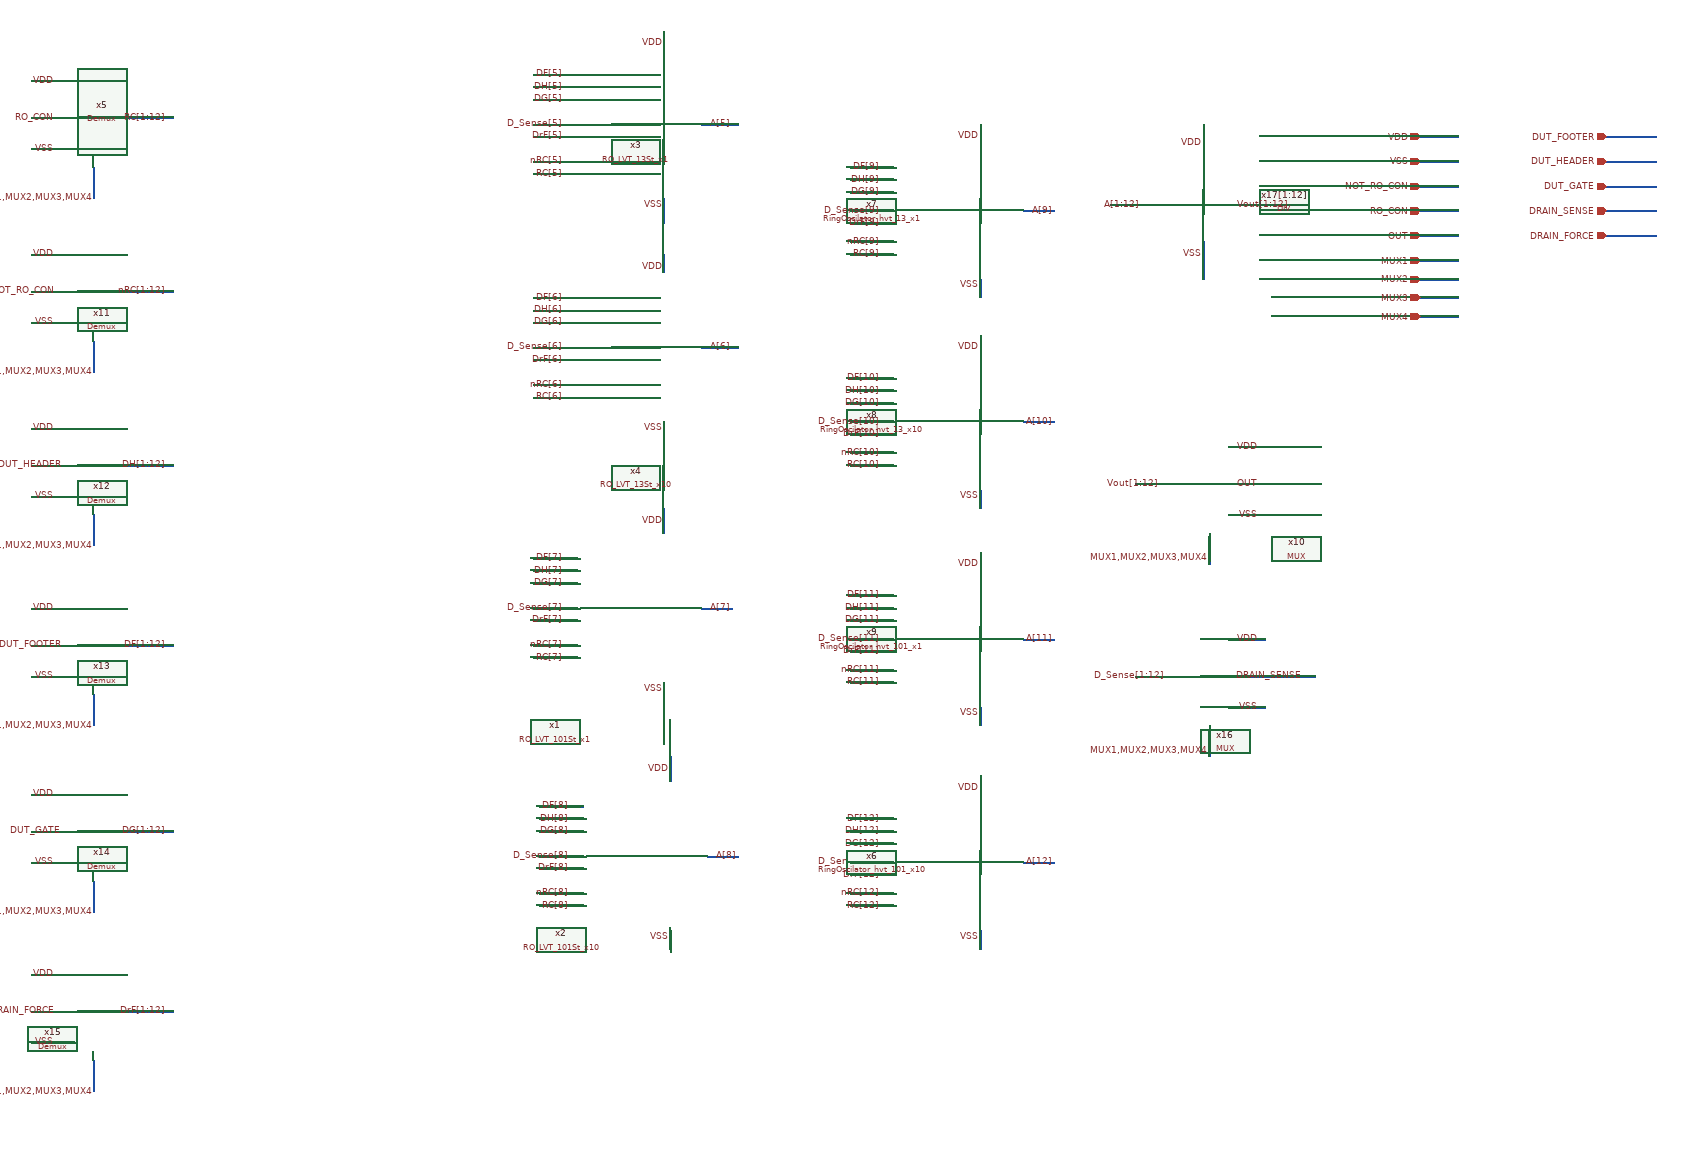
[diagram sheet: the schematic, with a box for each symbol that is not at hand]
v {xschem version=3.4.6RC file_version=1.2
}
G {}
K {}
V {}
S {}
E {}
N -850 650 -850 690 {
lab=VDD}
N -1060 730 -990 730 {
lab=DF[8]}
N -1060 750 -990 750 {
lab=DH[8]}
N -1060 770 -990 770 {
lab=DG[8]}
N -1060 810 -990 810 {
lab=D_Sense[8]}
N -1060 830 -990 830 {
lab=DrF[8]}
N -1060 870 -990 870 {
lab=nRC[8]}
N -1060 890 -990 890 {
lab=RC[8]}
N -790 810 -740 810 {
lab=A[8]}
N -850 930 -850 960 {
lab=VSS}
N -860 -520 -860 -490 {
lab=VDD}
N -860 -250 -860 -210 {
lab=VSS}
N -800 -370 -740 -370 {
lab=A[5]}
N 360 -350 420 -350 {
lab=VDD}
N 360 -310 420 -310 {
lab=VSS}
N 360 -270 420 -270 {
lab=NOT_RO_CON}
N 360 -230 420 -230 {
lab=RO_CON}
N 660 -350 740 -350 {
lab=DUT_FOOTER}
N 660 -310 740 -310 {
lab=DUT_HEADER}
N 660 -270 740 -270 {
lab=DUT_GATE}
N 660 -230 740 -230 {
lab=DRAIN_SENSE}
N 660 -190 740 -190 {
lab=DRAIN_FORCE}
N 360 -190 420 -190 {
lab=OUT}
N 360 -150 420 -150 {
lab=MUX1}
N -860 -160 -860 -130 {
lab=VDD}
N -860 110 -860 150 {
lab=VSS}
N -800 -10 -740 -10 {
lab=A[6]}
N -860 250 -860 290 {
lab=VDD}
N -800 410 -750 410 {
lab=A[7]}
N -860 530 -860 560 {
lab=VSS}
N -350 320 -350 360 {
lab=VDD}
N -280 460 -230 460 {
lab=A[11]}
N -350 570 -350 600 {
lab=VSS}
N -350 680 -350 720 {
lab=VDD}
N -560 750 -490 750 {
lab=DF[12]}
N -560 770 -490 770 {
lab=DH[12]}
N -560 790 -490 790 {
lab=DG[12]}
N -560 820 -490 820 {
lab=D_Sense[12]}
N -560 840 -490 840 {
lab=DrF[12]}
N -560 870 -490 870 {
lab=nRC[12]}
N -560 890 -490 890 {
lab=RC[12]}
N -280 820 -230 820 {
lab=A[12]}
N -350 930 -350 960 {
lab=VSS}
N -350 -370 -350 -330 {
lab=VDD}
N -280 -230 -230 -230 {
lab=A[9]}
N -350 -120 -350 -90 {
lab=VSS}
N -350 -30 -350 10 {
lab=VDD}
N -280 110 -230 110 {
lab=A[10]}
N -350 220 -350 250 {
lab=VSS}
N 50 150 110 150 {
lab=VDD}
N 50 210 110 210 {
lab=OUT}
N 50 260 110 260 {
lab=VSS}
N 20 290 20 340 {
lab=MUX1,MUX2,MUX3,MUX4}
N -100 210 -20 210 {
lab=Vout[1:12]}
N -1880 -380 -1810 -380 {
lab=RO_CON}
N -1880 -330 -1810 -330 {
lab=VSS}
N -1880 -440 -1810 -440 {
lab=VDD}
N -1780 -300 -1780 -250 {
lab=MUX1,MUX2,MUX3,MUX4}
N -1740 -380 -1650 -380 {
lab=RC[1:12]}
N -1880 -100 -1810 -100 {
lab=NOT_RO_CON}
N -1880 -50 -1810 -50 {
lab=VSS}
N -1880 -160 -1810 -160 {
lab=VDD}
N -1780 -20 -1780 30 {
lab=MUX1,MUX2,MUX3,MUX4}
N -1740 -100 -1650 -100 {
lab=nRC[1:12]}
N -1880 180 -1810 180 {
lab=DUT_HEADER}
N -1880 230 -1810 230 {
lab=VSS}
N -1880 120 -1810 120 {
lab=VDD}
N -1780 260 -1780 310 {
lab=MUX1,MUX2,MUX3,MUX4}
N -1740 180 -1650 180 {
lab=DH[1:12]}
N -1880 470 -1810 470 {
lab=DUT_FOOTER}
N -1880 520 -1810 520 {
lab=VSS}
N -1880 410 -1810 410 {
lab=VDD}
N -1780 550 -1780 600 {
lab=MUX1,MUX2,MUX3,MUX4}
N -1740 470 -1650 470 {
lab=DF[1:12]}
N -1880 770 -1810 770 {
lab=DUT_GATE}
N -1880 820 -1810 820 {
lab=VSS}
N -1880 710 -1810 710 {
lab=VDD}
N -1780 850 -1780 900 {
lab=MUX1,MUX2,MUX3,MUX4}
N -1740 770 -1650 770 {
lab=DG[1:12]}
N -1880 1060 -1810 1060 {
lab=DRAIN_FORCE}
N -1880 1110 -1810 1110 {
lab=VSS}
N -1880 1000 -1810 1000 {
lab=VDD}
N -1780 1140 -1780 1190 {
lab=MUX1,MUX2,MUX3,MUX4}
N -1740 1060 -1650 1060 {
lab=DrF[1:12]}
N 360 -120 420 -120 {
lab=MUX2}
N 360 -90 420 -90 {
lab=MUX3}
N 360 -60 420 -60 {
lab=MUX4}
N 50 460 110 460 {
lab=VDD}
N 50 520 110 520 {
lab=DRAIN_SENSE}
N 50 570 110 570 {
lab=VSS}
N 20 600 20 650 {
lab=MUX1,MUX2,MUX3,MUX4}
N -100 520 -20 520 {
lab=D_Sense[1:12]}
N 110 520 190 520 {
lab=DRAIN_SENSE}
N -560 390 -490 390 {
lab=DF[11]}
N -560 410 -490 410 {
lab=DH[11]}
N -560 430 -490 430 {
lab=DG[11]}
N -560 460 -490 460 {
lab=D_Sense[11]}
N -560 480 -490 480 {
lab=DrF[11]}
N -560 510 -490 510 {
lab=nRC[11]}
N -560 530 -490 530 {
lab=RC[11]}
N -560 40 -490 40 {
lab=DF[10]}
N -560 60 -490 60 {
lab=DH[10]}
N -560 80 -490 80 {
lab=DG[10]}
N -560 110 -490 110 {
lab=D_Sense[10]}
N -560 130 -490 130 {
lab=DrF[10]}
N -560 160 -490 160 {
lab=nRC[10]}
N -560 180 -490 180 {
lab=RC[10]}
N -560 -300 -490 -300 {
lab=DF[9]}
N -560 -280 -490 -280 {
lab=DH[9]}
N -560 -260 -490 -260 {
lab=DG[9]}
N -560 -230 -490 -230 {
lab=D_Sense[9]}
N -560 -210 -490 -210 {
lab=DrF[9]}
N -560 -180 -490 -180 {
lab=nRC[9]}
N -560 -160 -490 -160 {
lab=RC[9]}
N -1070 330 -1000 330 {
lab=DF[7]}
N -1070 350 -1000 350 {
lab=DH[7]}
N -1070 370 -1000 370 {
lab=DG[7]}
N -1070 410 -1000 410 {
lab=D_Sense[7]}
N -1070 430 -1000 430 {
lab=DrF[7]}
N -1070 470 -1000 470 {
lab=nRC[7]}
N -1070 490 -1000 490 {
lab=RC[7]}
N -1070 -90 -1000 -90 {
lab=DF[6]}
N -1070 -70 -1000 -70 {
lab=DH[6]}
N -1070 -50 -1000 -50 {
lab=DG[6]}
N -1070 -10 -1000 -10 {
lab=D_Sense[6]}
N -1070 10 -1000 10 {
lab=DrF[6]}
N -1070 50 -1000 50 {
lab=nRC[6]}
N -1070 70 -1000 70 {
lab=RC[6]}
N -1070 -450 -1000 -450 {
lab=DF[5]}
N -1070 -430 -1000 -430 {
lab=DH[5]}
N -1070 -410 -1000 -410 {
lab=DG[5]}
N -1070 -370 -1000 -370 {
lab=D_Sense[5]}
N -1070 -350 -1000 -350 {
lab=DrF[5]}
N -1070 -310 -1000 -310 {
lab=nRC[5]}
N -1070 -290 -1000 -290 {
lab=RC[5]}
N -140 -240 -60 -240 {
lab=#net1}
N 10 -180 10 -120 {
lab=#net2}
N 10 -370 10 -300 {
lab=#net3}
N 60 -240 150 -240 {
lab=#net4}
C {lab_wire.sym} -850 670 0 0 {name=p2 sig_type=std_logic lab=VDD}
C {lab_wire.sym} -860 -500 0 0 {name=p3 sig_type=std_logic lab=VDD}
C {lab_wire.sym} -860 -240 2 1 {name=p4 sig_type=std_logic lab=VSS}
C {lab_wire.sym} -850 940 2 1 {name=p5 sig_type=std_logic lab=VSS}
C {lab_wire.sym} -740 810 0 0 {name=p29 sig_type=std_logic lab=A[8]}
C {lab_wire.sym} -750 -370 0 0 {name=p30 sig_type=std_logic lab=A[5]}
C {iopin.sym} 360 -350 2 0 {name=p81 lab=VDD}
C {iopin.sym} 360 -310 2 0 {name=p82 lab=VSS}
C {iopin.sym} 360 -270 2 0 {name=p83 lab=NOT_RO_CON}
C {iopin.sym} 360 -230 2 0 {name=p84 lab=RO_CON}
C {iopin.sym} 660 -350 2 0 {name=p85 lab=DUT_FOOTER}
C {iopin.sym} 660 -310 2 0 {name=p86 lab=DUT_HEADER}
C {iopin.sym} 660 -270 2 0 {name=p87 lab=DUT_GATE}
C {iopin.sym} 660 -230 2 0 {name=p88 lab=DRAIN_SENSE}
C {iopin.sym} 660 -190 2 0 {name=p89 lab=DRAIN_FORCE}
C {iopin.sym} 360 -190 2 0 {name=p90 lab=OUT}
C {iopin.sym} 360 -150 2 0 {name=p37 lab=MUX1}
C {/foss/designs/RO_Aging_UNICASS/LVT/RO_LVT_101St_x10/RO_LVT_101St_x10.sym} -990 930 0 0 {name=x2}
C {/foss/designs/RO_Aging_UNICASS/LVT/RO_LVT_13St_x1/RO_LVT_13St_x1.sym} -1020 -250 0 0 {name=x3}
C {lab_wire.sym} -860 -140 0 0 {name=p38 sig_type=std_logic lab=VDD}
C {lab_wire.sym} -860 120 2 1 {name=p39 sig_type=std_logic lab=VSS}
C {lab_wire.sym} -750 -10 0 0 {name=p47 sig_type=std_logic lab=A[6]}
C {/foss/designs/RO_Aging_UNICASS/LVT/RO_LVT_13St_x10/RO_LVT_13St_x10.sym} -1020 110 0 0 {name=x4}
C {lab_wire.sym} -860 270 0 0 {name=p1 sig_type=std_logic lab=VDD}
C {lab_wire.sym} -860 540 2 1 {name=p6 sig_type=std_logic lab=VSS}
C {lab_wire.sym} -750 410 0 0 {name=p48 sig_type=std_logic lab=A[7]}
C {/foss/designs/RO_Aging_UNICASS/LVT/RO_LVT_101St_x1/RO_LVT_101St_x1.sym} -1000 530 0 0 {name=x1}
C {lab_wire.sym} -350 340 0 0 {name=p78 sig_type=std_logic lab=VDD}
C {lab_wire.sym} -350 580 2 1 {name=p79 sig_type=std_logic lab=VSS}
C {lab_wire.sym} -230 460 0 0 {name=p97 sig_type=std_logic lab=A[11]}
C {/foss/designs/RO_Aging_UNICASS/HVT/RingOscilator_hvt_101_x1/RingOscilator_hvt_101_x1.sym} -380 460 0 0 {name=x9}
C {lab_wire.sym} -350 700 0 0 {name=p28 sig_type=std_logic lab=VDD}
C {lab_wire.sym} -350 940 2 1 {name=p49 sig_type=std_logic lab=VSS}
C {lab_wire.sym} -510 770 0 0 {name=p50 sig_type=std_logic lab=DH[12]}
C {lab_wire.sym} -510 750 0 0 {name=p51 sig_type=std_logic lab=DF[12]}
C {lab_wire.sym} -510 790 0 0 {name=p52 sig_type=std_logic lab=DG[12]}
C {lab_wire.sym} -510 820 0 0 {name=p53 sig_type=std_logic lab=D_Sense[12]}
C {lab_wire.sym} -510 840 0 0 {name=p54 sig_type=std_logic lab=DrF[12]}
C {lab_wire.sym} -230 820 0 0 {name=p57 sig_type=std_logic lab=A[12]}
C {lab_wire.sym} -350 -350 0 0 {name=p58 sig_type=std_logic lab=VDD}
C {lab_wire.sym} -350 -110 2 1 {name=p59 sig_type=std_logic lab=VSS}
C {lab_wire.sym} -230 -230 0 0 {name=p67 sig_type=std_logic lab=A[9]}
C {lab_wire.sym} -350 -10 0 0 {name=p68 sig_type=std_logic lab=VDD}
C {lab_wire.sym} -350 230 2 1 {name=p69 sig_type=std_logic lab=VSS}
C {lab_wire.sym} -230 110 0 0 {name=p77 sig_type=std_logic lab=A[10]}
C {/foss/designs/RO_Aging_UNICASS/HVT/RingOscilator_hvt_101_x10/RingOscilator_hvt_101_x10.sym} -380 820 0 0 {name=x6}
C {/foss/designs/RO_Aging_UNICASS/HVT/RingOscilator_hvt_13_x1/RingOscilator_hvt_13_x1.sym} -380 -230 0 0 {name=x7}
C {/foss/designs/RO_Aging_UNICASS/HVT/RingOscilator_hvt_13_x10/RingOscilator_hvt_13_x10.sym} -380 110 0 0 {name=x8}
C {/foss/designs/RO_Aging_UNICASS/MUX/MUX.sym} 0 200 0 0 {name=x10}
C {lab_wire.sym} 100 150 0 0 {name=p31 sig_type=std_logic lab=VDD}
C {lab_wire.sym} 100 260 2 1 {name=p32 sig_type=std_logic lab=VSS}
C {lab_wire.sym} 100 210 0 0 {name=p33 sig_type=std_logic lab=OUT}
C {/foss/designs/RO_Aging_UNICASS/MUX/Demux.sym} -1780 -220 0 0 {name=x5}
C {lab_wire.sym} -1840 -440 0 0 {name=p34 sig_type=std_logic lab=VDD}
C {lab_wire.sym} -1840 -330 0 0 {name=p35 sig_type=std_logic lab=VSS}
C {lab_wire.sym} -1840 -380 0 0 {name=p36 sig_type=std_logic lab=RO_CON}
C {lab_wire.sym} -1780 -250 0 0 {name=p98 sig_type=std_logic lab=MUX1,MUX2,MUX3,MUX4}
C {/foss/designs/RO_Aging_UNICASS/MUX/Demux.sym} -1780 60 0 0 {name=x11}
C {lab_wire.sym} -1840 -160 0 0 {name=p99 sig_type=std_logic lab=VDD}
C {lab_wire.sym} -1840 -50 0 0 {name=p100 sig_type=std_logic lab=VSS}
C {lab_wire.sym} -1840 -100 0 0 {name=p101 sig_type=std_logic lab=NOT_RO_CON}
C {lab_wire.sym} -1780 30 0 0 {name=p102 sig_type=std_logic lab=MUX1,MUX2,MUX3,MUX4}
C {/foss/designs/RO_Aging_UNICASS/MUX/Demux.sym} -1780 340 0 0 {name=x12}
C {lab_wire.sym} -1840 120 0 0 {name=p103 sig_type=std_logic lab=VDD}
C {lab_wire.sym} -1840 230 0 0 {name=p104 sig_type=std_logic lab=VSS}
C {lab_wire.sym} -1780 310 0 0 {name=p106 sig_type=std_logic lab=MUX1,MUX2,MUX3,MUX4}
C {/foss/designs/RO_Aging_UNICASS/MUX/Demux.sym} -1780 630 0 0 {name=x13}
C {lab_wire.sym} -1840 410 0 0 {name=p107 sig_type=std_logic lab=VDD}
C {lab_wire.sym} -1840 520 0 0 {name=p108 sig_type=std_logic lab=VSS}
C {lab_wire.sym} -1780 600 0 0 {name=p110 sig_type=std_logic lab=MUX1,MUX2,MUX3,MUX4}
C {/foss/designs/RO_Aging_UNICASS/MUX/Demux.sym} -1780 930 0 0 {name=x14}
C {lab_wire.sym} -1840 710 0 0 {name=p111 sig_type=std_logic lab=VDD}
C {lab_wire.sym} -1840 820 0 0 {name=p112 sig_type=std_logic lab=VSS}
C {lab_wire.sym} -1780 900 0 0 {name=p114 sig_type=std_logic lab=MUX1,MUX2,MUX3,MUX4}
C {/foss/designs/RO_Aging_UNICASS/MUX/Demux.sym} -1780 1220 0 0 {name=x15}
C {lab_wire.sym} -1840 1000 0 0 {name=p115 sig_type=std_logic lab=VDD}
C {lab_wire.sym} -1840 1110 0 0 {name=p116 sig_type=std_logic lab=VSS}
C {lab_wire.sym} -1780 1190 0 0 {name=p118 sig_type=std_logic lab=MUX1,MUX2,MUX3,MUX4}
C {lab_wire.sym} -1830 180 0 0 {name=p105 sig_type=std_logic lab=DUT_HEADER}
C {lab_wire.sym} -1830 470 0 0 {name=p109 sig_type=std_logic lab=DUT_FOOTER}
C {lab_wire.sym} -1830 770 0 0 {name=p113 sig_type=std_logic lab=DUT_GATE}
C {lab_wire.sym} -1840 1060 0 0 {name=p117 sig_type=std_logic lab=DRAIN_FORCE}
C {iopin.sym} 360 -120 2 0 {name=p119 lab=MUX2}
C {iopin.sym} 360 -90 2 0 {name=p120 lab=MUX3}
C {iopin.sym} 360 -60 2 0 {name=p121 lab=MUX4}
C {/foss/designs/RO_Aging_UNICASS/MUX/MUX.sym} 0 510 0 0 {name=x16}
C {lab_wire.sym} 100 460 0 0 {name=p122 sig_type=std_logic lab=VDD}
C {lab_wire.sym} 100 570 2 1 {name=p123 sig_type=std_logic lab=VSS}
C {lab_wire.sym} 170 520 0 0 {name=p124 sig_type=std_logic lab=DRAIN_SENSE}
C {lab_wire.sym} 20 330 0 0 {name=p125 sig_type=std_logic lab=MUX1,MUX2,MUX3,MUX4}
C {lab_wire.sym} 20 640 0 0 {name=p126 sig_type=std_logic lab=MUX1,MUX2,MUX3,MUX4}
C {lab_wire.sym} -1660 -380 0 0 {name=p127 sig_type=std_logic lab=RC[1:12]}
C {lab_wire.sym} -1660 -100 0 0 {name=p128 sig_type=std_logic lab=nRC[1:12]}
C {lab_wire.sym} -1660 180 0 0 {name=p129 sig_type=std_logic lab=DH[1:12]}
C {lab_wire.sym} -1660 470 0 0 {name=p130 sig_type=std_logic lab=DF[1:12]}
C {lab_wire.sym} -1660 770 0 0 {name=p131 sig_type=std_logic lab=DG[1:12]}
C {lab_wire.sym} -1660 1060 0 0 {name=p132 sig_type=std_logic lab=DrF[1:12]}
C {lab_wire.sym} -510 890 0 0 {name=p133 sig_type=std_logic lab=RC[12]}
C {lab_wire.sym} -510 870 0 0 {name=p55 sig_type=std_logic lab=nRC[12]}
C {lab_wire.sym} -50 520 0 0 {name=p56 sig_type=std_logic lab=D_Sense[1:12]}
C {lab_wire.sym} -60 210 0 0 {name=p134 sig_type=std_logic lab=Vout[1:12]}
C {lab_wire.sym} -510 410 0 0 {name=p80 sig_type=std_logic lab=DH[11]}
C {lab_wire.sym} -510 390 0 0 {name=p91 sig_type=std_logic lab=DF[11]}
C {lab_wire.sym} -510 430 0 0 {name=p92 sig_type=std_logic lab=DG[11]}
C {lab_wire.sym} -510 460 0 0 {name=p93 sig_type=std_logic lab=D_Sense[11]}
C {lab_wire.sym} -510 480 0 0 {name=p94 sig_type=std_logic lab=DrF[11]}
C {lab_wire.sym} -510 530 0 0 {name=p95 sig_type=std_logic lab=RC[11]}
C {lab_wire.sym} -510 510 0 0 {name=p96 sig_type=std_logic lab=nRC[11]}
C {lab_wire.sym} -510 60 0 0 {name=p70 sig_type=std_logic lab=DH[10]}
C {lab_wire.sym} -510 40 0 0 {name=p71 sig_type=std_logic lab=DF[10]}
C {lab_wire.sym} -510 80 0 0 {name=p72 sig_type=std_logic lab=DG[10]}
C {lab_wire.sym} -510 110 0 0 {name=p73 sig_type=std_logic lab=D_Sense[10]}
C {lab_wire.sym} -510 130 0 0 {name=p74 sig_type=std_logic lab=DrF[10]}
C {lab_wire.sym} -510 180 0 0 {name=p75 sig_type=std_logic lab=RC[10]}
C {lab_wire.sym} -510 160 0 0 {name=p76 sig_type=std_logic lab=nRC[10]}
C {lab_wire.sym} -510 -280 0 0 {name=p60 sig_type=std_logic lab=DH[9]}
C {lab_wire.sym} -510 -300 0 0 {name=p61 sig_type=std_logic lab=DF[9]}
C {lab_wire.sym} -510 -260 0 0 {name=p62 sig_type=std_logic lab=DG[9]}
C {lab_wire.sym} -510 -230 0 0 {name=p63 sig_type=std_logic lab=D_Sense[9]}
C {lab_wire.sym} -510 -210 0 0 {name=p64 sig_type=std_logic lab=DrF[9]}
C {lab_wire.sym} -510 -160 0 0 {name=p65 sig_type=std_logic lab=RC[9]}
C {lab_wire.sym} -510 -180 0 0 {name=p66 sig_type=std_logic lab=nRC[9]}
C {lab_wire.sym} -1010 890 0 0 {name=p14 sig_type=std_logic lab=RC[8]}
C {lab_wire.sym} -1010 870 0 0 {name=p15 sig_type=std_logic lab=nRC[8]}
C {lab_wire.sym} -1010 810 0 0 {name=p16 sig_type=std_logic lab=D_Sense[8]}
C {lab_wire.sym} -1010 830 0 0 {name=p17 sig_type=std_logic lab=DrF[8]}
C {lab_wire.sym} -1010 750 0 0 {name=p18 sig_type=std_logic lab=DH[8]}
C {lab_wire.sym} -1010 730 0 0 {name=p19 sig_type=std_logic lab=DF[8]}
C {lab_wire.sym} -1010 770 0 0 {name=p20 sig_type=std_logic lab=DG[8]}
C {lab_wire.sym} -1020 490 0 0 {name=p7 sig_type=std_logic lab=RC[7]}
C {lab_wire.sym} -1020 470 0 0 {name=p8 sig_type=std_logic lab=nRC[7]}
C {lab_wire.sym} -1020 410 0 0 {name=p9 sig_type=std_logic lab=D_Sense[7]}
C {lab_wire.sym} -1020 430 0 0 {name=p10 sig_type=std_logic lab=DrF[7]}
C {lab_wire.sym} -1020 350 0 0 {name=p11 sig_type=std_logic lab=DH[7]}
C {lab_wire.sym} -1020 330 0 0 {name=p12 sig_type=std_logic lab=DF[7]}
C {lab_wire.sym} -1020 370 0 0 {name=p13 sig_type=std_logic lab=DG[7]}
C {lab_wire.sym} -1020 70 0 0 {name=p40 sig_type=std_logic lab=RC[6]}
C {lab_wire.sym} -1020 50 0 0 {name=p41 sig_type=std_logic lab=nRC[6]}
C {lab_wire.sym} -1020 -10 0 0 {name=p42 sig_type=std_logic lab=D_Sense[6]}
C {lab_wire.sym} -1020 10 0 0 {name=p43 sig_type=std_logic lab=DrF[6]}
C {lab_wire.sym} -1020 -70 0 0 {name=p44 sig_type=std_logic lab=DH[6]}
C {lab_wire.sym} -1020 -90 0 0 {name=p45 sig_type=std_logic lab=DF[6]}
C {lab_wire.sym} -1020 -50 0 0 {name=p46 sig_type=std_logic lab=DG[6]}
C {lab_wire.sym} -1020 -290 0 0 {name=p21 sig_type=std_logic lab=RC[5]}
C {lab_wire.sym} -1020 -310 0 0 {name=p22 sig_type=std_logic lab=nRC[5]}
C {lab_wire.sym} -1020 -370 0 0 {name=p23 sig_type=std_logic lab=D_Sense[5]}
C {lab_wire.sym} -1020 -350 0 0 {name=p24 sig_type=std_logic lab=DrF[5]}
C {lab_wire.sym} -1020 -430 0 0 {name=p25 sig_type=std_logic lab=DH[5]}
C {lab_wire.sym} -1020 -450 0 0 {name=p26 sig_type=std_logic lab=DF[5]}
C {lab_wire.sym} -1020 -410 0 0 {name=p27 sig_type=std_logic lab=DG[5]}
C {/foss/designs/RO_Aging_UNICASS/DIV/DIV.sym} -100 -170 0 0 {name=x17[1:12]}
C {lab_wire.sym} 150 -240 0 0 {name=p135 sig_type=std_logic lab=Vout[1:12]}
C {lab_wire.sym} -90 -240 0 0 {name=p136 sig_type=std_logic lab=A[1:12]}
C {lab_wire.sym} 10 -340 0 0 {name=p137 sig_type=std_logic lab=VDD}
C {lab_wire.sym} 10 -160 2 1 {name=p138 sig_type=std_logic lab=VSS}
